! (c) 2009  Infineon Technologies AG, Munich
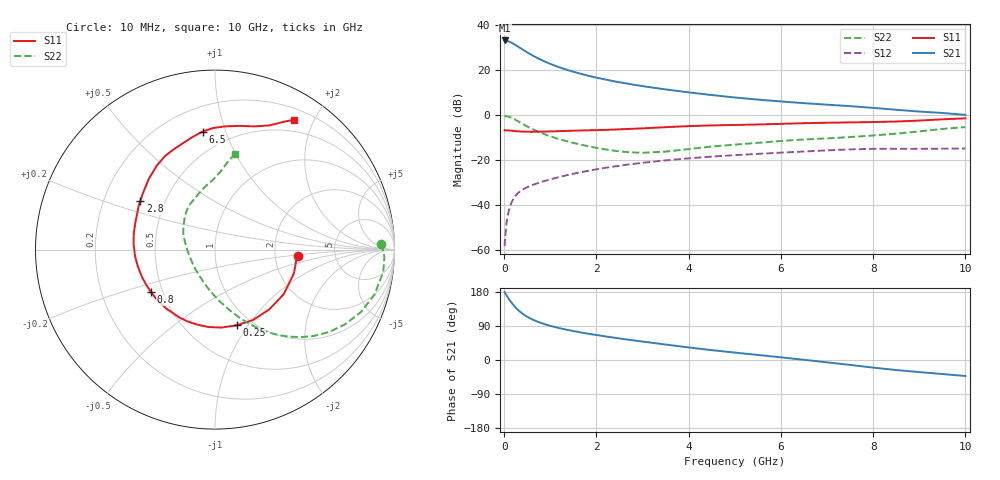
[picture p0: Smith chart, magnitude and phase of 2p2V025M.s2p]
! Infineon Technologies  Discrete & RF Semiconductors
! BFP420
! VCE =  2.0 V,  IC =  25 mA
! Common Emitter S-Parameters:  Nov 2009
# GHz  S  MA  R  50
!  f  S11  S21  S12  S22
! GHz  MAG  ANG  MAG  ANG  MAG  ANG  MAG  ANG
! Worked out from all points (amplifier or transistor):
!   46 points, 10 MHz to 10 GHz, reference 50 ohm
!   highest |S21| = 33.3 dB at 10 MHz (marker M1)
!   |S21| within 3 dB of that: start of sweep to 321.5 MHz
!   unconditionally stable (mu >= 1): 1.635 GHz to end of sweep
!   at 300 MHz: K = 0.36, MSG = 32.7 dB, |S12| = -34.8 dB
!   at 1.7 GHz: K = 1.01, MAG = 21.1 dB, |S12| = -25.3 dB
!   at 10 GHz: K = 1.06, MAG = 6.0 dB, |S12| = -14.9 dB
!   lowest NFmin = 1.38 dB at 900 MHz
!   S11 on the Smith chart (normalised r, x): 10 MHz: 2.69, -0.25; 250 MHz: 0.85, -0.89; 800 MHz: 0.43, -0.25; 2.8 GHz: 0.36, +0.26; 6.5 GHz: 0.36, +0.83; 10 GHz: 0.34, +1.73
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0.01  0.4619 -4.6  46.23 179.3  0.0012 111.0  0.9278 1.9
0.02  0.4569 -6.9  45.34 176.3  0.0018 94.0  0.9446 -2.4
0.05  0.4593 -16.6  44.99 170.6  0.0039 84.2  0.9458 -7.5
0.1  0.4566 -33.0  43.81 161.4  0.0074 79.6  0.9235 -15.8
0.15  0.4499 -48.0  41.66 152.9  0.0107 74.2  0.8835 -23.3
0.2  0.4459 -61.6  39.14 145.2  0.0136 69.9  0.8348 -30.0
0.25  0.4386 -74.1  36.36 138.2  0.0161 66.5  0.7834 -35.9
0.3  0.436 -85.2  33.82 132.2  0.0183 63.7  0.7316 -41.1
0.4  0.4295 -103.4  29.05 122.1  0.0219 59.7  0.6379 -49.5
0.5  0.4268 -117.8  25.06 114.2  0.0248 57.4  0.5593 -56.2
0.6  0.426 -129.3  21.84 107.6  0.0274 56.1  0.496 -61.6
0.8  0.4283 -146.3  17.1 97.7  0.0322 55.1  0.4028 -70.2
1  0.434 -158.8  13.91 90.1  0.037 54.8  0.3381 -77.6
1.2  0.4404 -168.4  11.63 84.0  0.0418 54.6  0.2911 -84.4
1.7  0.4562 173.9  8.155 72.0  0.0544 53.0  0.2159 -101.1
2.8  0.4969 146.8  4.786 51.9  0.0818 45.4  0.1474 -146.7
3.5  0.5392 133.3  3.747 40.8  0.098 39.2  0.154 -178.3
5.5  0.6191 106.8  2.222 13.3  0.137 20.7  0.2414 134.8
6.5  0.6612 96.0  1.851 0.5  0.1547 11.5  0.2869 120.0
7  0.6776 90.8  1.711 -6.2  0.164 6.6  0.3033 112.7
8.5  0.7206 72.3  1.317 -26.5  0.1776 -10.5  0.3862 92.2
10  0.8475 58.6  1.015 -42.2  0.1806 -21.7  0.542 78.4
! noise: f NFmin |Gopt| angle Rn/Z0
0.9  1.38  0.22  -154  0.13
1.8  1.65  0.29  -143  0.13
2.4  1.81  0.26  -138  0.17
3  1.83  0.34  -129  0.18
4  1.97  0.45  -112  0.27
5  2.4  0.49  -95  0.44
6  2.85  0.54  -84  0.65
